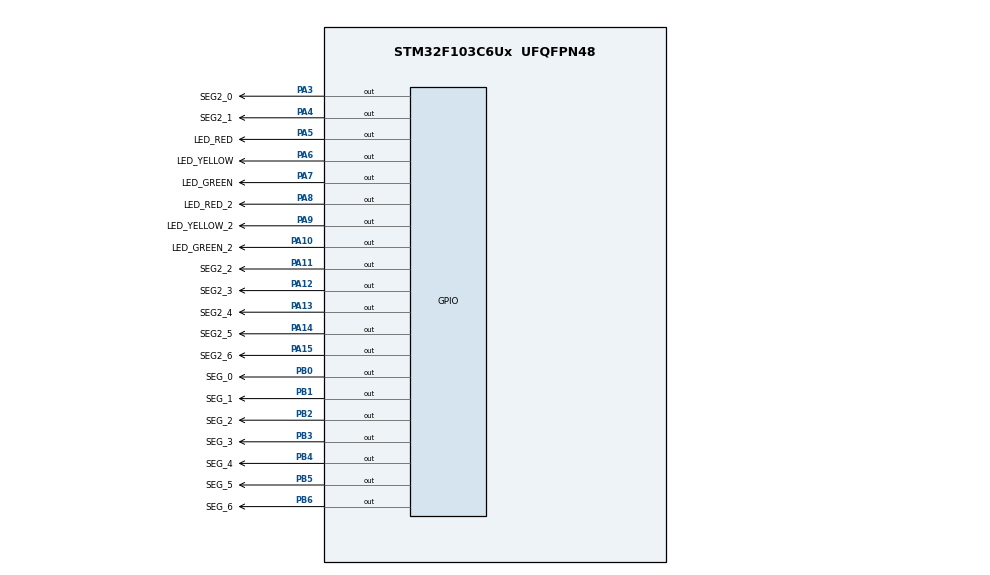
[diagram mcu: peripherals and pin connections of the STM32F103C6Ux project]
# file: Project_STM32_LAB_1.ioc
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Mcu.Family=STM32F1
Mcu.Name=STM32F103C6Ux
Mcu.Package=UFQFPN48
NVIC.PriorityGroup=NVIC_PRIORITYGROUP_4
PA10.GPIO_Label=LED_GREEN_2
PA10.Signal=GPIO_Output
PA11.GPIO_Label=SEG2_2
PA11.Signal=GPIO_Output
PA12.GPIO_Label=SEG2_3
PA12.Signal=GPIO_Output
PA13.GPIO_Label=SEG2_4
PA13.Signal=GPIO_Output
PA14.GPIO_Label=SEG2_5
PA14.Signal=GPIO_Output
PA15.GPIO_Label=SEG2_6
PA15.Signal=GPIO_Output
PA3.GPIO_Label=SEG2_0
PA3.Signal=GPIO_Output
PA4.GPIO_Label=SEG2_1
PA4.Signal=GPIO_Output
PA5.GPIO_Label=LED_RED
PA5.Signal=GPIO_Output
PA6.GPIO_Label=LED_YELLOW
PA6.Signal=GPIO_Output
PA7.GPIO_Label=LED_GREEN
PA7.Signal=GPIO_Output
PA8.GPIO_Label=LED_RED_2
PA8.Signal=GPIO_Output
PA9.GPIO_Label=LED_YELLOW_2
PA9.Signal=GPIO_Output
PB0.GPIO_Label=SEG_0
PB0.Signal=GPIO_Output
PB1.GPIO_Label=SEG_1
PB1.Signal=GPIO_Output
PB2.GPIO_Label=SEG_2
PB2.Signal=GPIO_Output
PB3.GPIO_Label=SEG_3
PB3.Signal=GPIO_Output
PB4.GPIO_Label=SEG_4
PB4.Signal=GPIO_Output
PB5.GPIO_Label=SEG_5
PB5.Signal=GPIO_Output
PB6.GPIO_Label=SEG_6
PB6.Signal=GPIO_Output
ProjectManager.HeapSize=0x200
ProjectManager.StackSize=0x400
ProjectManager.TargetToolchain=STM32CubeIDE
RCC.APB1Freq_Value=8000000
RCC.APB2Freq_Value=8000000
VP_SYS_VS_ND.Mode=No_Debug
board=custom

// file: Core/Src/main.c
/* USER CODE BEGIN Header */
/**
  ******************************************************************************
  * @file           : main.c
  * @brief          : Main program body
  ******************************************************************************
  * @attention
  *
  * <h2><center>&copy; Copyright (c) 2024 STMicroelectronics.
  * All rights reserved.</center></h2>
  *
  * This software component is licensed by ST under BSD 3-Clause license,
  * the "License"; You may not use this file except in compliance with the
  * License. You may obtain a copy of the License at:
  *                        opensource.org/licenses/BSD-3-Clause
  *
  ******************************************************************************
  */
/* USER CODE END Header */
#include "main.h"

/* USER CODE BEGIN Includes */
//#include "exercise1.h"
//#include "exercise2.h"
//#include "exercise3.h"
//#include "exercise4.h"
//#include "exercise5.h"
#include "exercise6.h"
#include "exercise10.h"
/* USER CODE END Includes */

void SystemClock_Config(void);
static void MX_GPIO_Init(void);

int main(void)
{

  /* MCU Configuration--------------------------------------------------------*/

  /* Reset of all peripherals, Initializes the Flash interface and the Systick. */
  HAL_Init();

  /* Configure the system clock */
  SystemClock_Config();

  /* Initialize all configured peripherals */
  MX_GPIO_Init();

  /* Infinite loop */
  /* USER CODE BEGIN WHILE */
//  InitExercise1();
//  InitExercise2();
//  InitExercise3();
//  InitExercise4();
//  InitExercise6();
  InitExercise10();
  while (1)
  {
//	  RunExercise1();
//	  RunExercise2();
//	  RunExercise3();
//	  RunExercise4();
//	  RunExercise5();
//	  RunExercise6();
//	  setNumberOnClock(7);
//	  display7Seg2(4);
	  RunExercise10();

	  HAL_Delay(100);
    /* USER CODE END WHILE */

  }
}

void SystemClock_Config(void)
{
  RCC_OscInitTypeDef RCC_OscInitStruct = {0};
  RCC_ClkInitTypeDef RCC_ClkInitStruct = {0};

  /** Initializes the RCC Oscillators according to the specified parameters
  * in the RCC_OscInitTypeDef structure.
  */
  RCC_OscInitStruct.OscillatorType = RCC_OSCILLATORTYPE_HSI;
  RCC_OscInitStruct.HSIState = RCC_HSI_ON;
  RCC_OscInitStruct.HSICalibrationValue = RCC_HSICALIBRATION_DEFAULT;
  RCC_OscInitStruct.PLL.PLLState = RCC_PLL_NONE;
  if (HAL_RCC_OscConfig(&RCC_OscInitStruct) != HAL_OK)
  {
    Error_Handler();
  }
  /** Initializes the CPU, AHB and APB buses clocks
  */
  RCC_ClkInitStruct.ClockType = RCC_CLOCKTYPE_HCLK|RCC_CLOCKTYPE_SYSCLK
                              |RCC_CLOCKTYPE_PCLK1|RCC_CLOCKTYPE_PCLK2;
  RCC_ClkInitStruct.SYSCLKSource = RCC_SYSCLKSOURCE_HSI;
  RCC_ClkInitStruct.AHBCLKDivider = RCC_SYSCLK_DIV1;
  RCC_ClkInitStruct.APB1CLKDivider = RCC_HCLK_DIV1;
  RCC_ClkInitStruct.APB2CLKDivider = RCC_HCLK_DIV1;

  if (HAL_RCC_ClockConfig(&RCC_ClkInitStruct, FLASH_LATENCY_0) != HAL_OK)
  {
    Error_Handler();
  }
}

static void MX_GPIO_Init(void)
{
  GPIO_InitTypeDef GPIO_InitStruct = {0};

  /* GPIO Ports Clock Enable */
  __HAL_RCC_GPIOA_CLK_ENABLE();
  __HAL_RCC_GPIOB_CLK_ENABLE();

  /*Configure GPIO pin Output Level */
  HAL_GPIO_WritePin(GPIOA, SEG2_0_Pin|SEG2_1_Pin|SEG2_2_Pin|LED_Clock_0_Pin
                          |LED_RED_Pin|LED_YELLOW_Pin|LED_GREEN_Pin|LED_RED_2_Pin
                          |LED_YELLOW_2_Pin|LED_GREEN_2_Pin|LED_Clock_7_Pin|LED_Clock_8_Pin
                          |LED_Clock_9_Pin|LED_Clock_10_Pin|LED_Clock_11_Pin, GPIO_PIN_RESET);

  /*Configure GPIO pin Output Level */
  HAL_GPIO_WritePin(GPIOB, SEG_0_Pin|SEG_1_Pin|SEG_2_Pin|SEG2_6_Pin
                          |SEG_3_Pin|SEG_4_Pin|SEG_5_Pin|SEG_6_Pin
                          |SEG2_3_Pin|SEG2_4_Pin|SEG2_5_Pin, GPIO_PIN_RESET);

  /*Configure GPIO pins : SEG2_0_Pin SEG2_1_Pin SEG2_2_Pin LED_Clock_0_Pin
                           LED_RED_Pin LED_YELLOW_Pin LED_GREEN_Pin LED_RED_2_Pin
                           LED_YELLOW_2_Pin LED_GREEN_2_Pin LED_Clock_7_Pin LED_Clock_8_Pin
                           LED_Clock_9_Pin LED_Clock_10_Pin LED_Clock_11_Pin */
  GPIO_InitStruct.Pin = SEG2_0_Pin|SEG2_1_Pin|SEG2_2_Pin|LED_Clock_0_Pin
                          |LED_RED_Pin|LED_YELLOW_Pin|LED_GREEN_Pin|LED_RED_2_Pin
                          |LED_YELLOW_2_Pin|LED_GREEN_2_Pin|LED_Clock_7_Pin|LED_Clock_8_Pin
                          |LED_Clock_9_Pin|LED_Clock_10_Pin|LED_Clock_11_Pin;
  GPIO_InitStruct.Mode = GPIO_MODE_OUTPUT_PP;
  GPIO_InitStruct.Pull = GPIO_NOPULL;
  GPIO_InitStruct.Speed = GPIO_SPEED_FREQ_LOW;
  HAL_GPIO_Init(GPIOA, &GPIO_InitStruct);

  /*Configure GPIO pins : SEG_0_Pin SEG_1_Pin SEG_2_Pin SEG2_6_Pin
                           SEG_3_Pin SEG_4_Pin SEG_5_Pin SEG_6_Pin
                           SEG2_3_Pin SEG2_4_Pin SEG2_5_Pin */
  GPIO_InitStruct.Pin = SEG_0_Pin|SEG_1_Pin|SEG_2_Pin|SEG2_6_Pin
                          |SEG_3_Pin|SEG_4_Pin|SEG_5_Pin|SEG_6_Pin
                          |SEG2_3_Pin|SEG2_4_Pin|SEG2_5_Pin;
  GPIO_InitStruct.Mode = GPIO_MODE_OUTPUT_PP;
  GPIO_InitStruct.Pull = GPIO_NOPULL;
  GPIO_InitStruct.Speed = GPIO_SPEED_FREQ_LOW;
  HAL_GPIO_Init(GPIOB, &GPIO_InitStruct);

}

void Error_Handler(void)
{
  __disable_irq();
  while (1)
  {
  }
}

/************************ (C) COPYRIGHT STMicroelectronics *****END OF FILE****/
